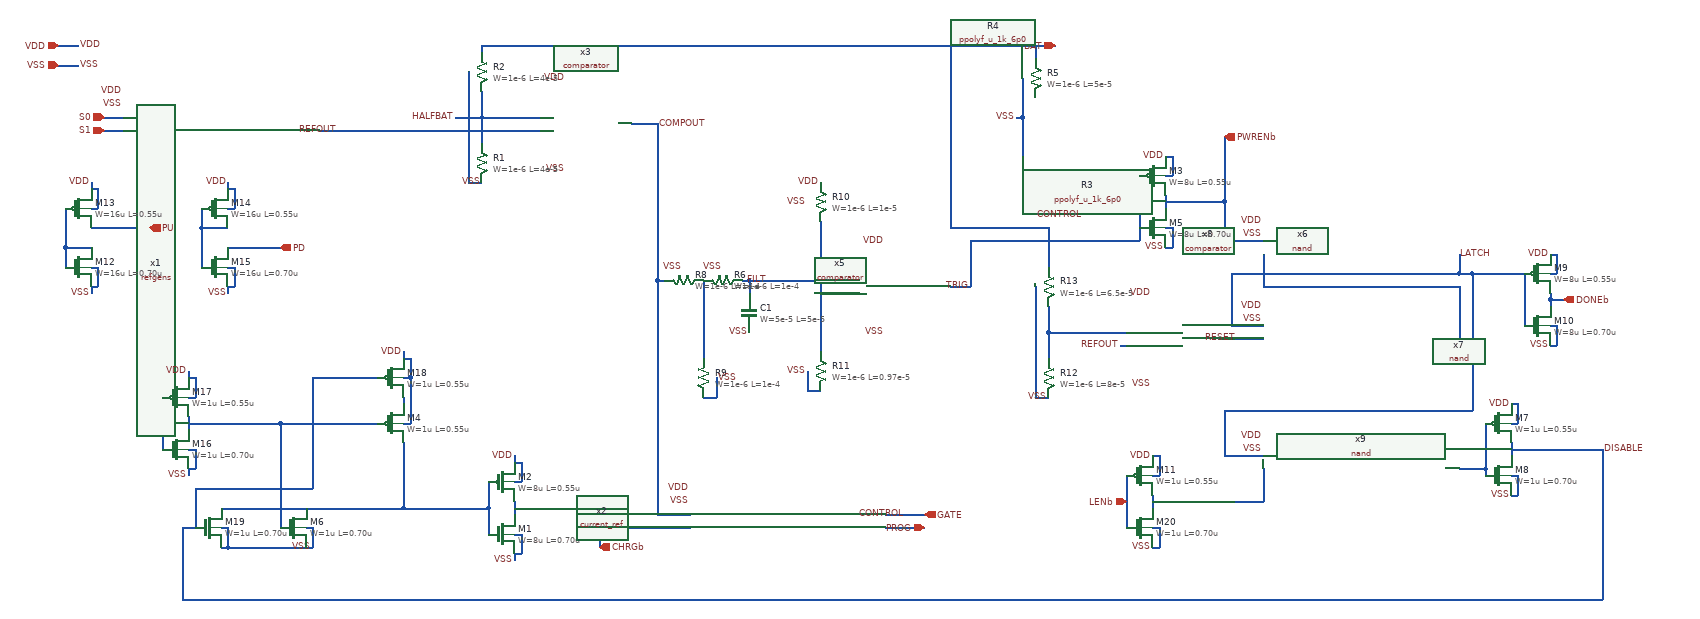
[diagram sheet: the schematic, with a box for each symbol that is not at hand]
v {xschem version=3.4.8RC file_version=1.3}
G {}
K {}
V {}
S {}
F {}
E {}
N -110 -10 -80 -10 {lab=VDD}
N -110 20 -80 20 {lab=VSS}
N -40 100 -10 100 {lab=S0}
N -40 120 -10 120 {lab=S1}
N 1160 710 1220 710 {lab=GATE}
N 590 690 590 710 {lab=CHRGb}
N 590 620 590 630 {lab=VDD}
N 590 660 600 660 {lab=VDD}
N 600 630 600 660 {lab=VDD}
N 590 630 600 630 {lab=VDD}
N 590 740 600 740 {lab=VSS}
N 600 740 600 770 {lab=VSS}
N 590 770 600 770 {lab=VSS}
N 590 770 590 780 {lab=VSS}
N 420 600 420 610 {lab=#net1}
N 420 530 420 540 {lab=#net2}
N 420 570 430 570 {lab=VDD}
N 270 730 280 730 {lab=VSS}
N 280 730 280 760 {lab=VSS}
N 230 570 380 570 {lab=#net3}
N 270 700 420 700 {lab=#net1}
N 420 670 420 700 {lab=#net1}
N 550 660 550 700 {lab=#net1}
N 550 700 550 740 {lab=#net1}
N 420 700 550 700 {lab=#net1}
N 720 730 860 730 {lab=CHRGb}
N 720 700 720 730 {lab=CHRGb}
N 590 700 720 700 {lab=CHRGb}
N 520 170 520 200 {lab=VSS}
N 520 200 540 200 {lab=VSS}
N 540 100 630 100 {lab=HALFBAT}
N 540 100 540 140 {lab=HALFBAT}
N 520 30 520 170 {lab=VSS}
N 540 60 540 100 {lab=HALFBAT}
N 540 -10 540 -0 {lab=BAT}
N 500 100 540 100 {lab=HALFBAT}
N 1360 100 1370 100 {lab=VSS}
N 1370 40 1370 100 {lab=VSS}
N 1370 100 1370 160 {lab=VSS}
N -60 360 -60 370 {lab=VSS}
N -100 300 -100 330 {lab=#net4}
N -100 300 -60 300 {lab=#net4}
N -60 360 -50 360 {lab=VSS}
N -50 330 -50 360 {lab=VSS}
N -60 330 -50 330 {lab=VSS}
N -100 240 -100 300 {lab=#net4}
N -60 240 -50 240 {lab=VDD}
N -50 210 -50 240 {lab=VDD}
N -60 210 -50 210 {lab=VDD}
N -60 200 -60 210 {lab=VDD}
N -60 270 30 270 {lab=PU}
N 150 200 150 210 {lab=VDD}
N 150 240 160 240 {lab=VDD}
N 160 210 160 240 {lab=VDD}
N 150 210 160 210 {lab=VDD}
N 110 240 110 270 {lab=#net5}
N 110 270 150 270 {lab=#net5}
N 110 270 110 330 {lab=#net5}
N 150 330 160 330 {lab=VSS}
N 160 330 160 360 {lab=VSS}
N 150 360 160 360 {lab=VSS}
N 150 360 150 370 {lab=VSS}
N 150 300 230 300 {lab=PD}
N 90 560 90 580 {lab=#net3}
N 90 490 90 500 {lab=VDD}
N 90 530 100 530 {lab=VDD}
N 100 500 100 530 {lab=VDD}
N 90 500 100 500 {lab=VDD}
N 90 610 100 610 {lab=VSS}
N 100 610 100 640 {lab=VSS}
N 90 640 100 640 {lab=VSS}
N 90 640 90 650 {lab=VSS}
N 50 530 50 570 {lab=CE}
N 50 570 50 610 {lab=CE}
N 90 570 230 570 {lab=#net3}
N 420 460 420 470 {lab=VDD}
N 420 500 430 500 {lab=VDD}
N 430 470 430 500 {lab=VDD}
N 420 470 430 470 {lab=VDD}
N 430 500 430 570 {lab=VDD}
N 140 700 270 700 {lab=#net1}
N 140 730 150 730 {lab=VSS}
N 150 730 150 760 {lab=VSS}
N 140 760 150 760 {lab=VSS}
N 150 760 270 760 {lab=VSS}
N 100 670 100 730 {lab=DISABLE}
N 100 670 280 670 {lab=DISABLE}
N 280 500 280 670 {lab=DISABLE}
N 280 500 380 500 {lab=DISABLE}
N 230 570 230 730 {lab=#net3}
N 80 730 100 730 {lab=DISABLE}
N 290 120 300 120 {lab=REFOUT}
N 1160 730 1220 730 {lab=PROG}
N 420 610 420 670 {lab=#net1}
N 270 760 280 760 {lab=VSS}
N 770 110 810 110 {lab=COMPOUT}
N 300 120 320 120 {lab=REFOUT}
N 320 120 630 120 {lab=REFOUT}
N 540 -10 1420 -10 {lab=BAT}
N 950 350 950 370 {lab=FILT}
N 950 350 980 350 {lab=FILT}
N 940 350 950 350 {lab=FILT}
N 880 350 880 470 {lab=#net6}
N 880 530 900 530 {lab=VSS}
N 900 500 900 530 {lab=VSS}
N 1260 360 1290 360 {lab=TRIG}
N 980 350 1120 350 {lab=FILT}
N 1040 520 1060 520 {lab=VSS}
N 1040 490 1040 520 {lab=VSS}
N 1060 260 1060 460 {lab=#net7}
N 1060 370 1120 370 {lab=#net7}
N 2040 310 2040 340 {lab=LATCH}
N 1690 340 2040 340 {lab=LATCH}
N 1690 340 1690 420 {lab=LATCH}
N 1690 420 1740 420 {lab=LATCH}
N 1740 310 1740 360 {lab=#net8}
N 1740 360 2040 360 {lab=#net8}
N 2040 360 2040 440 {lab=#net8}
N 1290 290 1290 360 {lab=TRIG}
N 1670 440 1740 440 {lab=RESET}
N 1390 500 1390 530 {lab=VSS}
N 1390 530 1410 530 {lab=VSS}
N 1410 430 1410 470 {lab=#net9}
N 1390 360 1390 500 {lab=VSS}
N 1410 390 1410 430 {lab=#net9}
N 1410 320 1410 330 {lab=BAT}
N 1410 270 1410 320 {lab=BAT}
N 1260 270 1410 270 {lab=BAT}
N 1260 -10 1260 270 {lab=BAT}
N 1410 430 1530 430 {lab=#net9}
N 1520 450 1530 450 {lab=REFOUT}
N 1590 190 1600 190 {lab=VDD}
N 1600 160 1600 190 {lab=VDD}
N 1590 160 1600 160 {lab=VDD}
N 1590 270 1600 270 {lab=VSS}
N 1600 270 1600 300 {lab=VSS}
N 1590 300 1600 300 {lab=VSS}
N 1590 220 1590 240 {lab=PWRENb}
N 1290 290 1550 290 {lab=TRIG}
N 1550 190 1550 290 {lab=TRIG}
N 1590 230 1680 230 {lab=PWRENb}
N 1680 230 1680 290 {lab=PWRENb}
N 1680 290 1740 290 {lab=PWRENb}
N 2120 600 2120 620 {lab=DISABLE}
N 2040 640 2080 640 {lab=#net10}
N 2080 640 2080 650 {lab=#net10}
N 2080 570 2080 640 {lab=#net10}
N 2120 570 2130 570 {lab=VDD}
N 2130 540 2130 570 {lab=VDD}
N 2120 540 2130 540 {lab=VDD}
N 2120 650 2130 650 {lab=VSS}
N 2130 650 2130 680 {lab=VSS}
N 2120 680 2130 680 {lab=VSS}
N 2040 340 2060 340 {lab=LATCH}
N 2060 340 2060 550 {lab=LATCH}
N 1680 550 2060 550 {lab=LATCH}
N 1680 550 1680 620 {lab=LATCH}
N 1680 620 1740 620 {lab=LATCH}
N 80 730 80 840 {lab=DISABLE}
N 80 840 2260 840 {lab=DISABLE}
N 2260 610 2260 840 {lab=DISABLE}
N 2120 610 2260 610 {lab=DISABLE}
N 2180 380 2200 380 {lab=DONEb}
N 2180 370 2180 380 {lab=DONEb}
N 2180 380 2180 390 {lab=DONEb}
N 2140 340 2140 420 {lab=LATCH}
N 2060 340 2140 340 {lab=LATCH}
N 2180 340 2190 340 {lab=VDD}
N 2190 310 2190 340 {lab=VDD}
N 2180 310 2190 310 {lab=VDD}
N 2180 450 2190 450 {lab=VSS}
N 2190 420 2190 450 {lab=VSS}
N 2180 420 2190 420 {lab=VSS}
N 1570 680 1570 700 {lab=#net11}
N 1570 650 1580 650 {lab=VDD}
N 1580 620 1580 650 {lab=VDD}
N 1570 620 1580 620 {lab=VDD}
N 1570 730 1580 730 {lab=VSS}
N 1580 730 1580 760 {lab=VSS}
N 1570 760 1580 760 {lab=VSS}
N 1530 650 1530 730 {lab=LENb}
N 1740 640 1740 690 {lab=#net11}
N 1570 690 1740 690 {lab=#net11}
N 1390 -10 1390 10 {lab=BAT}
N 1680 130 1680 230 {lab=PWRENb}
N 810 350 820 350 {lab=COMPOUT}
N 810 110 810 350 {lab=COMPOUT}
N 720 730 720 760 {lab=CHRGb}
N 810 350 810 710 {lab=COMPOUT}
N 810 710 860 710 {lab=COMPOUT}
C {iopin.sym} -110 -10 2 0 {name=p1 lab=VDD}
C {lab_pin.sym} -80 -10 2 0 {name=p2 sig_type=std_logic lab=VDD}
C {iopin.sym} -110 20 2 0 {name=p3 lab=VSS}
C {lab_pin.sym} -80 20 2 0 {name=p4 sig_type=std_logic lab=VSS}
C {ipin.sym} -40 100 0 0 {name=p5 lab=S0}
C {ipin.sym} -40 120 0 0 {name=p6 lab=S1}
C {ipin.sym} 1530 690 0 0 {name=p7 lab=LENb}
C {ipin.sym} 50 570 0 0 {name=p8 lab=CE}
C {opin.sym} 720 760 0 0 {name=p9 lab=CHRGb}
C {opin.sym} 2200 380 0 0 {name=p10 lab=DONEb}
C {iopin.sym} 1220 730 0 0 {name=p11 lab=PROG}
C {opin.sym} 1680 130 0 0 {name=p12 lab=PWRENb}
C {refgens.sym} 140 100 0 0 {name=x1}
C {lab_pin.sym} -10 60 0 0 {name=p13 sig_type=std_logic lab=VDD}
C {lab_pin.sym} -10 80 0 0 {name=p14 sig_type=std_logic lab=VSS}
C {opin.sym} 1220 710 0 0 {name=p15 lab=GATE}
C {ipin.sym} 1420 -10 2 0 {name=p16 lab=BAT}
C {current_ref.sym} 1010 700 0 0 {name=x2}
C {lab_pin.sym} 860 670 0 0 {name=p17 sig_type=std_logic lab=VDD}
C {symbols/nfet_06v0.sym} 570 740 0 0 {name=M1
L=0.70u
W=8u
nf=1
m=1
ad="'int((nf+1)/2) * W/nf * 0.18u'"
pd="'2*int((nf+1)/2) * (W/nf + 0.18u)'"
as="'int((nf+2)/2) * W/nf * 0.18u'"
ps="'2*int((nf+2)/2) * (W/nf + 0.18u)'"
nrd="'0.18u / W'" nrs="'0.18u / W'"
sa=0 sb=0 sd=0
model=nfet_06v0
spiceprefix=X
}
C {symbols/pfet_06v0.sym} 570 660 0 0 {name=M2
L=0.55u
W=8u
nf=1
m=1
ad="'int((nf+1)/2) * W/nf * 0.18u'"
pd="'2*int((nf+1)/2) * (W/nf + 0.18u)'"
as="'int((nf+2)/2) * W/nf * 0.18u'"
ps="'2*int((nf+2)/2) * (W/nf + 0.18u)'"
nrd="'0.18u / W'" nrs="'0.18u / W'"
sa=0 sb=0 sd=0
model=pfet_06v0
spiceprefix=X
}
C {lab_pin.sym} 590 620 1 0 {name=p19 sig_type=std_logic lab=VDD}
C {lab_pin.sym} 590 780 3 0 {name=p20 sig_type=std_logic lab=VSS}
C {symbols/pfet_06v0.sym} 400 570 0 0 {name=M4
L=0.55u
W=1u
nf=1
m=1
ad="'int((nf+1)/2) * W/nf * 0.18u'"
pd="'2*int((nf+1)/2) * (W/nf + 0.18u)'"
as="'int((nf+2)/2) * W/nf * 0.18u'"
ps="'2*int((nf+2)/2) * (W/nf + 0.18u)'"
nrd="'0.18u / W'" nrs="'0.18u / W'"
sa=0 sb=0 sd=0
model=pfet_06v0
spiceprefix=X
}
C {lab_pin.sym} 420 460 1 0 {name=p21 sig_type=std_logic lab=VDD}
C {lab_pin.sym} 280 760 3 0 {name=p22 sig_type=std_logic lab=VSS}
C {symbols/nfet_06v0.sym} 250 730 0 0 {name=M6
L=0.70u
W=1u
nf=1
m=1
ad="'int((nf+1)/2) * W/nf * 0.18u'"
pd="'2*int((nf+1)/2) * (W/nf + 0.18u)'"
as="'int((nf+2)/2) * W/nf * 0.18u'"
ps="'2*int((nf+2)/2) * (W/nf + 0.18u)'"
nrd="'0.18u / W'" nrs="'0.18u / W'"
sa=0 sb=0 sd=0
model=nfet_06v0
spiceprefix=X
}
C {lab_pin.sym} 670 40 1 0 {name=p23 sig_type=std_logic lab=VDD}
C {lab_pin.sym} 670 180 3 0 {name=p24 sig_type=std_logic lab=VSS}
C {symbols/ppolyf_u_1k_6p0.sym} 540 170 0 0 {name=R1
W=1e-6
L=4e-5
model=ppolyf_u_1k_6p0
spiceprefix=X
m=1}
C {lab_pin.sym} 540 200 3 0 {name=p25 sig_type=std_logic lab=VSS}
C {symbols/ppolyf_u_1k_6p0.sym} 540 30 0 0 {name=R2
W=1e-6
L=4e-5
model=ppolyf_u_1k_6p0
spiceprefix=X
m=1}
C {lab_pin.sym} 320 120 1 0 {name=p30 sig_type=std_logic lab=REFOUT}
C {lab_pin.sym} 500 100 0 0 {name=p31 sig_type=std_logic lab=HALFBAT}
C {symbols/diode_pd2nw_06v0.sym} 1390 220 0 0 {name=D1
model=diode_pd2nw_06v0
r_w=2u
r_l=1u
m=1}
C {symbols/ppolyf_u_1k_6p0.sym} 1390 160 0 0 {name=R3
W=1e-6
L=5e-5
model=ppolyf_u_1k_6p0
spiceprefix=X
m=1}
C {symbols/ppolyf_u_1k_6p0.sym} 1390 100 0 0 {name=R4
W=1e-6
L=5e-5
model=ppolyf_u_1k_6p0
spiceprefix=X
m=1}
C {symbols/ppolyf_u_1k_6p0.sym} 1390 40 0 0 {name=R5
W=1e-6
L=5e-5
model=ppolyf_u_1k_6p0
spiceprefix=X
m=1}
C {lab_pin.sym} 1360 100 0 0 {name=p32 sig_type=std_logic lab=VSS}
C {opin.sym} 30 270 0 0 {name=p34 lab=PU}
C {opin.sym} 230 300 0 0 {name=p35 lab=PD}
C {symbols/nfet_06v0.sym} -80 330 0 0 {name=M12
L=0.70u
W=16u
nf=2
m=1
ad="'int((nf+1)/2) * W/nf * 0.18u'"
pd="'2*int((nf+1)/2) * (W/nf + 0.18u)'"
as="'int((nf+2)/2) * W/nf * 0.18u'"
ps="'2*int((nf+2)/2) * (W/nf + 0.18u)'"
nrd="'0.18u / W'" nrs="'0.18u / W'"
sa=0 sb=0 sd=0
model=nfet_06v0
spiceprefix=X
}
C {lab_pin.sym} -60 370 3 0 {name=p38 sig_type=std_logic lab=VSS}
C {symbols/pfet_06v0.sym} -80 240 0 0 {name=M13
L=0.55u
W=16u
nf=2
m=1
ad="'int((nf+1)/2) * W/nf * 0.18u'"
pd="'2*int((nf+1)/2) * (W/nf + 0.18u)'"
as="'int((nf+2)/2) * W/nf * 0.18u'"
ps="'2*int((nf+2)/2) * (W/nf + 0.18u)'"
nrd="'0.18u / W'" nrs="'0.18u / W'"
sa=0 sb=0 sd=0
model=pfet_06v0
spiceprefix=X
}
C {lab_pin.sym} -60 200 1 0 {name=p39 sig_type=std_logic lab=VDD}
C {symbols/pfet_06v0.sym} 130 240 0 0 {name=M14
L=0.55u
W=16u
nf=2
m=1
ad="'int((nf+1)/2) * W/nf * 0.18u'"
pd="'2*int((nf+1)/2) * (W/nf + 0.18u)'"
as="'int((nf+2)/2) * W/nf * 0.18u'"
ps="'2*int((nf+2)/2) * (W/nf + 0.18u)'"
nrd="'0.18u / W'" nrs="'0.18u / W'"
sa=0 sb=0 sd=0
model=pfet_06v0
spiceprefix=X
}
C {lab_pin.sym} 150 200 1 0 {name=p40 sig_type=std_logic lab=VDD}
C {symbols/nfet_06v0.sym} 130 330 0 0 {name=M15
L=0.70u
W=16u
nf=2
m=1
ad="'int((nf+1)/2) * W/nf * 0.18u'"
pd="'2*int((nf+1)/2) * (W/nf + 0.18u)'"
as="'int((nf+2)/2) * W/nf * 0.18u'"
ps="'2*int((nf+2)/2) * (W/nf + 0.18u)'"
nrd="'0.18u / W'" nrs="'0.18u / W'"
sa=0 sb=0 sd=0
model=nfet_06v0
spiceprefix=X
}
C {lab_pin.sym} 150 370 3 0 {name=p41 sig_type=std_logic lab=VSS}
C {symbols/nfet_06v0.sym} 70 610 0 0 {name=M16
L=0.70u
W=1u
nf=1
m=1
ad="'int((nf+1)/2) * W/nf * 0.18u'"
pd="'2*int((nf+1)/2) * (W/nf + 0.18u)'"
as="'int((nf+2)/2) * W/nf * 0.18u'"
ps="'2*int((nf+2)/2) * (W/nf + 0.18u)'"
nrd="'0.18u / W'" nrs="'0.18u / W'"
sa=0 sb=0 sd=0
model=nfet_06v0
spiceprefix=X
}
C {symbols/pfet_06v0.sym} 70 530 0 0 {name=M17
L=0.55u
W=1u
nf=1
m=1
ad="'int((nf+1)/2) * W/nf * 0.18u'"
pd="'2*int((nf+1)/2) * (W/nf + 0.18u)'"
as="'int((nf+2)/2) * W/nf * 0.18u'"
ps="'2*int((nf+2)/2) * (W/nf + 0.18u)'"
nrd="'0.18u / W'" nrs="'0.18u / W'"
sa=0 sb=0 sd=0
model=pfet_06v0
spiceprefix=X
}
C {lab_pin.sym} 90 490 1 0 {name=p42 sig_type=std_logic lab=VDD}
C {lab_pin.sym} 90 650 3 0 {name=p43 sig_type=std_logic lab=VSS}
C {symbols/pfet_06v0.sym} 400 500 0 0 {name=M18
L=0.55u
W=1u
nf=1
m=1
ad="'int((nf+1)/2) * W/nf * 0.18u'"
pd="'2*int((nf+1)/2) * (W/nf + 0.18u)'"
as="'int((nf+2)/2) * W/nf * 0.18u'"
ps="'2*int((nf+2)/2) * (W/nf + 0.18u)'"
nrd="'0.18u / W'" nrs="'0.18u / W'"
sa=0 sb=0 sd=0
model=pfet_06v0
spiceprefix=X
}
C {symbols/nfet_06v0.sym} 120 730 0 0 {name=M19
L=0.70u
W=1u
nf=1
m=1
ad="'int((nf+1)/2) * W/nf * 0.18u'"
pd="'2*int((nf+1)/2) * (W/nf + 0.18u)'"
as="'int((nf+2)/2) * W/nf * 0.18u'"
ps="'2*int((nf+2)/2) * (W/nf + 0.18u)'"
nrd="'0.18u / W'" nrs="'0.18u / W'"
sa=0 sb=0 sd=0
model=nfet_06v0
spiceprefix=X
}
C {lab_pin.sym} 860 690 0 0 {name=p18 sig_type=std_logic lab=VSS}
C {lab_pin.sym} 810 110 2 0 {name=p28 sig_type=std_logic lab=COMPOUT}
C {lab_pin.sym} 950 430 3 0 {name=p33 sig_type=std_logic lab=VSS}
C {lab_pin.sym} 980 350 1 0 {name=p36 sig_type=std_logic lab=FILT}
C {symbols/cap_mim_2f0fF.sym} 950 400 0 0 {name=C1
W=5e-5
L=5e-5
model=cap_mim_2f0fF
spiceprefix=X
m=1}
C {symbols/ppolyf_u_1k_6p0.sym} 910 350 1 0 {name=R6
W=1e-6
L=1e-4
model=ppolyf_u_1k_6p0
spiceprefix=X
m=1}
C {lab_pin.sym} 910 330 1 0 {name=p37 sig_type=std_logic lab=VSS}
C {symbols/ppolyf_u_1k_6p0.sym} 850 350 1 0 {name=R8
W=1e-6
L=1e-4
model=ppolyf_u_1k_6p0
spiceprefix=X
m=1}
C {lab_pin.sym} 850 330 1 0 {name=p44 sig_type=std_logic lab=VSS}
C {symbols/ppolyf_u_1k_6p0.sym} 880 500 2 0 {name=R9
W=1e-6
L=1e-4
model=ppolyf_u_1k_6p0
spiceprefix=X
m=1}
C {lab_pin.sym} 900 500 2 0 {name=p47 sig_type=std_logic lab=VSS}
C {comparator.sym} 1270 360 0 0 {name=x5}
C {lab_pin.sym} 1160 290 1 0 {name=p45 sig_type=std_logic lab=VDD}
C {lab_pin.sym} 1160 430 3 0 {name=p46 sig_type=std_logic lab=VSS}
C {lab_pin.sym} 1290 360 3 0 {name=p49 sig_type=std_logic lab=TRIG}
C {symbols/ppolyf_u_1k_6p0.sym} 1060 230 0 0 {name=R10
W=1e-6
L=1e-5
model=ppolyf_u_1k_6p0
spiceprefix=X
m=1}
C {lab_pin.sym} 1040 230 0 0 {name=p48 sig_type=std_logic lab=VSS}
C {symbols/ppolyf_u_1k_6p0.sym} 1060 490 0 0 {name=R11
W=1e-6
L=0.97e-5
model=ppolyf_u_1k_6p0
spiceprefix=X
m=1}
C {lab_pin.sym} 1040 490 0 0 {name=p50 sig_type=std_logic lab=VSS}
C {lab_pin.sym} 1060 200 1 0 {name=p51 sig_type=std_logic lab=VDD}
C {nand.sym} 1890 290 0 0 {name=x6}
C {nand.sym} 1890 420 0 0 {name=x7}
C {lab_pin.sym} 1740 260 0 0 {name=p52 sig_type=std_logic lab=VDD}
C {lab_pin.sym} 1740 390 0 0 {name=p53 sig_type=std_logic lab=VDD}
C {lab_pin.sym} 1740 280 0 0 {name=p54 sig_type=std_logic lab=VSS}
C {lab_pin.sym} 1740 410 0 0 {name=p55 sig_type=std_logic lab=VSS}
C {comparator.sym} 1680 440 0 0 {name=x8}
C {lab_pin.sym} 1190 710 1 0 {name=p56 sig_type=std_logic lab=CONTROL}
C {lab_pin.sym} 1570 370 1 0 {name=p57 sig_type=std_logic lab=VDD}
C {lab_pin.sym} 1570 510 3 0 {name=p58 sig_type=std_logic lab=VSS}
C {lab_pin.sym} 1520 450 0 0 {name=p59 sig_type=std_logic lab=REFOUT}
C {symbols/ppolyf_u_1k_6p0.sym} 1410 500 0 0 {name=R12
W=1e-6
L=8e-5
model=ppolyf_u_1k_6p0
spiceprefix=X
m=1}
C {lab_pin.sym} 1410 530 3 0 {name=p60 sig_type=std_logic lab=VSS}
C {symbols/ppolyf_u_1k_6p0.sym} 1410 360 0 0 {name=R13
W=1e-6
L=6.5e-5
model=ppolyf_u_1k_6p0
spiceprefix=X
m=1}
C {lab_pin.sym} 1390 250 2 0 {name=p61 sig_type=std_logic lab=CONTROL}
C {lab_pin.sym} 1700 440 3 0 {name=p62 sig_type=std_logic lab=RESET}
C {lab_pin.sym} 2040 310 2 0 {name=p63 sig_type=std_logic lab=LATCH}
C {symbols/pfet_06v0.sym} 1570 190 0 0 {name=M3
L=0.55u
W=8u
nf=1
m=1
ad="'int((nf+1)/2) * W/nf * 0.18u'"
pd="'2*int((nf+1)/2) * (W/nf + 0.18u)'"
as="'int((nf+2)/2) * W/nf * 0.18u'"
ps="'2*int((nf+2)/2) * (W/nf + 0.18u)'"
nrd="'0.18u / W'" nrs="'0.18u / W'"
sa=0 sb=0 sd=0
model=pfet_06v0
spiceprefix=X
}
C {symbols/nfet_06v0.sym} 1570 270 0 0 {name=M5
L=0.70u
W=8u
nf=1
m=1
ad="'int((nf+1)/2) * W/nf * 0.18u'"
pd="'2*int((nf+1)/2) * (W/nf + 0.18u)'"
as="'int((nf+2)/2) * W/nf * 0.18u'"
ps="'2*int((nf+2)/2) * (W/nf + 0.18u)'"
nrd="'0.18u / W'" nrs="'0.18u / W'"
sa=0 sb=0 sd=0
model=nfet_06v0
spiceprefix=X
}
C {lab_pin.sym} 1590 160 1 0 {name=p64 sig_type=std_logic lab=VDD}
C {lab_pin.sym} 1590 300 3 0 {name=p65 sig_type=std_logic lab=VSS}
C {nand.sym} 1890 620 0 0 {name=x9}
C {lab_pin.sym} 1740 590 0 0 {name=p66 sig_type=std_logic lab=VDD}
C {lab_pin.sym} 1740 610 0 0 {name=p67 sig_type=std_logic lab=VSS}
C {symbols/pfet_06v0.sym} 2100 570 0 0 {name=M7
L=0.55u
W=1u
nf=1
m=1
ad="'int((nf+1)/2) * W/nf * 0.18u'"
pd="'2*int((nf+1)/2) * (W/nf + 0.18u)'"
as="'int((nf+2)/2) * W/nf * 0.18u'"
ps="'2*int((nf+2)/2) * (W/nf + 0.18u)'"
nrd="'0.18u / W'" nrs="'0.18u / W'"
sa=0 sb=0 sd=0
model=pfet_06v0
spiceprefix=X
}
C {symbols/nfet_06v0.sym} 2100 650 0 0 {name=M8
L=0.70u
W=1u
nf=1
m=1
ad="'int((nf+1)/2) * W/nf * 0.18u'"
pd="'2*int((nf+1)/2) * (W/nf + 0.18u)'"
as="'int((nf+2)/2) * W/nf * 0.18u'"
ps="'2*int((nf+2)/2) * (W/nf + 0.18u)'"
nrd="'0.18u / W'" nrs="'0.18u / W'"
sa=0 sb=0 sd=0
model=nfet_06v0
spiceprefix=X
}
C {lab_pin.sym} 2120 540 1 0 {name=p68 sig_type=std_logic lab=VDD}
C {lab_pin.sym} 2120 680 3 0 {name=p69 sig_type=std_logic lab=VSS}
C {lab_pin.sym} 2260 610 2 0 {name=p70 sig_type=std_logic lab=DISABLE}
C {symbols/pfet_06v0.sym} 2160 340 0 0 {name=M9
L=0.55u
W=8u
nf=1
m=1
ad="'int((nf+1)/2) * W/nf * 0.18u'"
pd="'2*int((nf+1)/2) * (W/nf + 0.18u)'"
as="'int((nf+2)/2) * W/nf * 0.18u'"
ps="'2*int((nf+2)/2) * (W/nf + 0.18u)'"
nrd="'0.18u / W'" nrs="'0.18u / W'"
sa=0 sb=0 sd=0
model=pfet_06v0
spiceprefix=X
}
C {symbols/nfet_06v0.sym} 2160 420 0 0 {name=M10
L=0.70u
W=8u
nf=1
m=1
ad="'int((nf+1)/2) * W/nf * 0.18u'"
pd="'2*int((nf+1)/2) * (W/nf + 0.18u)'"
as="'int((nf+2)/2) * W/nf * 0.18u'"
ps="'2*int((nf+2)/2) * (W/nf + 0.18u)'"
nrd="'0.18u / W'" nrs="'0.18u / W'"
sa=0 sb=0 sd=0
model=nfet_06v0
spiceprefix=X
}
C {lab_pin.sym} 2180 310 1 0 {name=p26 sig_type=std_logic lab=VDD}
C {lab_pin.sym} 2180 450 3 0 {name=p71 sig_type=std_logic lab=VSS}
C {symbols/pfet_06v0.sym} 1550 650 0 0 {name=M11
L=0.55u
W=1u
nf=1
m=1
ad="'int((nf+1)/2) * W/nf * 0.18u'"
pd="'2*int((nf+1)/2) * (W/nf + 0.18u)'"
as="'int((nf+2)/2) * W/nf * 0.18u'"
ps="'2*int((nf+2)/2) * (W/nf + 0.18u)'"
nrd="'0.18u / W'" nrs="'0.18u / W'"
sa=0 sb=0 sd=0
model=pfet_06v0
spiceprefix=X
}
C {symbols/nfet_06v0.sym} 1550 730 0 0 {name=M20
L=0.70u
W=1u
nf=1
m=1
ad="'int((nf+1)/2) * W/nf * 0.18u'"
pd="'2*int((nf+1)/2) * (W/nf + 0.18u)'"
as="'int((nf+2)/2) * W/nf * 0.18u'"
ps="'2*int((nf+2)/2) * (W/nf + 0.18u)'"
nrd="'0.18u / W'" nrs="'0.18u / W'"
sa=0 sb=0 sd=0
model=nfet_06v0
spiceprefix=X
}
C {lab_pin.sym} 1570 620 1 0 {name=p72 sig_type=std_logic lab=VDD}
C {lab_pin.sym} 1570 760 3 0 {name=p73 sig_type=std_logic lab=VSS}
C {comparator.sym} 780 110 0 0 {name=x3}
